One B-rep face of a CAD part: STEP entity #107.
In plain terms, the planar face has unit normal (1, 0, 0).
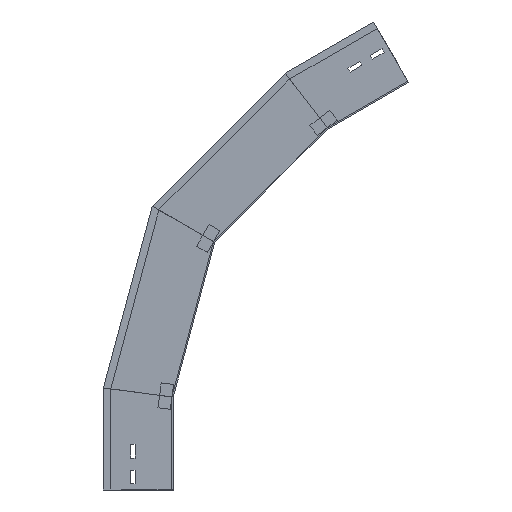
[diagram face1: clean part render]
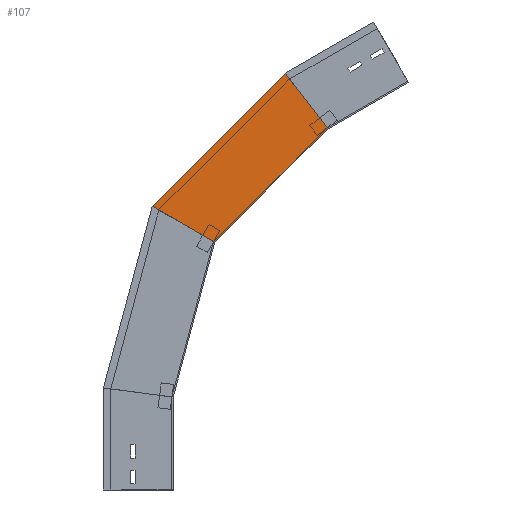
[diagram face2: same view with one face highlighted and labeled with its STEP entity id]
Its self-contained STEP definition (entity closure, numbers rounded to 3 decimals):
#41 = EDGE_CURVE ( 'NONE', #1145, #935, #890, .T. ) ;
#62 = LINE ( 'NONE', #711, #981 ) ;
#99 = DIRECTION ( 'NONE',  ( 0., -0.991, -0.131 ) ) ;
#107 = ADVANCED_FACE ( 'NONE', ( #360 ), #636, .T. ) ;
#125 = EDGE_CURVE ( 'NONE', #189, #1258, #520, .T. ) ;
#189 = VERTEX_POINT ( 'NONE', #919 ) ;
#212 = VECTOR ( 'NONE', #1494, 1000. ) ;
#231 = DIRECTION ( 'NONE',  ( 1., 0., 0. ) ) ;
#323 = DIRECTION ( 'NONE',  ( 0., -0.259, 0.966 ) ) ;
#353 = CARTESIAN_POINT ( 'NONE',  ( 0., -19.411, 147.444 ) ) ;
#360 = FACE_OUTER_BOUND ( 'NONE', #1163, .T. ) ;
#372 = CARTESIAN_POINT ( 'NONE',  ( 0., 4.243, 134.167 ) ) ;
#508 = CARTESIAN_POINT ( 'NONE',  ( 0., -128.762, 364.536 ) ) ;
#520 = LINE ( 'NONE', #508, #1093 ) ;
#636 = PLANE ( 'NONE',  #1172 ) ;
#662 = CARTESIAN_POINT ( 'NONE',  ( 0., 112.5, 164.811 ) ) ;
#711 = CARTESIAN_POINT ( 'NONE',  ( 0., 112.909, 163.284 ) ) ;
#778 = VECTOR ( 'NONE', #99, 1000. ) ;
#794 = EDGE_CURVE ( 'NONE', #935, #1258, #1203, .T. ) ;
#847 = EDGE_CURVE ( 'NONE', #1145, #189, #62, .T. ) ;
#877 = DIRECTION ( 'NONE',  ( 0., -0.866, -0.5 ) ) ;
#890 = LINE ( 'NONE', #353, #778 ) ;
#894 = CARTESIAN_POINT ( 'NONE',  ( 0., 0., 150. ) ) ;
#919 = CARTESIAN_POINT ( 'NONE',  ( 0., 33.831, 458.409 ) ) ;
#935 = VERTEX_POINT ( 'NONE', #894 ) ;
#960 = CARTESIAN_POINT ( 'NONE',  ( 0., 4.243, 134.167 ) ) ;
#981 = VECTOR ( 'NONE', #323, 1000. ) ;
#1093 = VECTOR ( 'NONE', #877, 1000. ) ;
#1141 = ORIENTED_EDGE ( 'NONE', *, *, #125, .T. ) ;
#1145 = VERTEX_POINT ( 'NONE', #662 ) ;
#1163 = EDGE_LOOP ( 'NONE', ( #1183, #1141, #1547, #1247 ) ) ;
#1172 = AXIS2_PLACEMENT_3D ( 'NONE', #372, #231, #1226 ) ;
#1183 = ORIENTED_EDGE ( 'NONE', *, *, #847, .T. ) ;
#1203 = LINE ( 'NONE', #960, #212 ) ;
#1211 = CARTESIAN_POINT ( 'NONE',  ( 0., -67.034, 400.175 ) ) ;
#1226 = DIRECTION ( 'NONE',  ( 0., 0., -1. ) ) ;
#1247 = ORIENTED_EDGE ( 'NONE', *, *, #41, .F. ) ;
#1258 = VERTEX_POINT ( 'NONE', #1211 ) ;
#1494 = DIRECTION ( 'NONE',  ( 0., -0.259, 0.966 ) ) ;
#1547 = ORIENTED_EDGE ( 'NONE', *, *, #794, .F. ) ;
